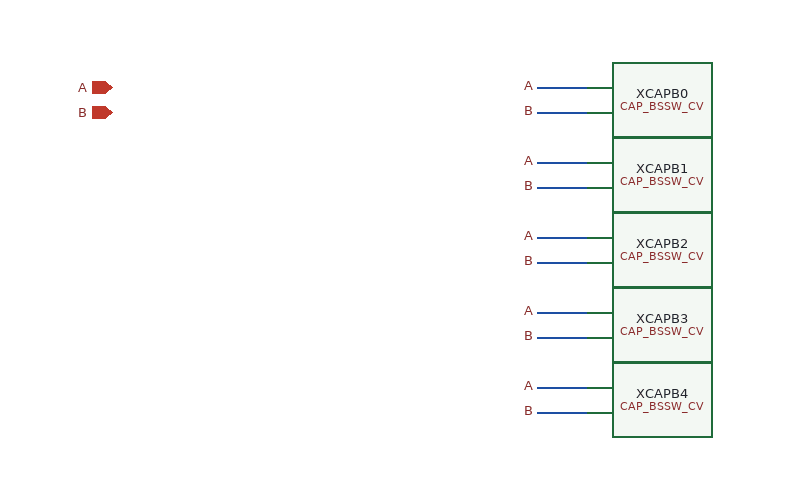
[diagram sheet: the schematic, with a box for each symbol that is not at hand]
v {xschem version=3.0.0 file_version=1.2 }
C {devices/iopin.sym} 0 0 0 0{name=p0 lab=A}
C {devices/iopin.sym} 0 20 0 0{name=p1 lab=B}
C {SUN_SAR9B_SK130NM/CAP_BSSW_CV.sym} 400 0 0 0 {name=XCAPB0}
N 340.0 0.0 380.0 0.0{lab=A}
C {devices/lab_pin.sym} 340.0 0.0 0 0  {name=l0 sig_type=std_logic lab=A }
N 340.0 20.0 380.0 20.0{lab=B}
C {devices/lab_pin.sym} 340.0 20.0 0 0  {name=l1 sig_type=std_logic lab=B }
C {SUN_SAR9B_SK130NM/CAP_BSSW_CV.sym} 400 60 0 0 {name=XCAPB1}
N 340.0 60.0 380.0 60.0{lab=A}
C {devices/lab_pin.sym} 340.0 60.0 0 0  {name=l2 sig_type=std_logic lab=A }
N 340.0 80.0 380.0 80.0{lab=B}
C {devices/lab_pin.sym} 340.0 80.0 0 0  {name=l3 sig_type=std_logic lab=B }
C {SUN_SAR9B_SK130NM/CAP_BSSW_CV.sym} 400 120 0 0 {name=XCAPB2}
N 340.0 120.0 380.0 120.0{lab=A}
C {devices/lab_pin.sym} 340.0 120.0 0 0  {name=l4 sig_type=std_logic lab=A }
N 340.0 140.0 380.0 140.0{lab=B}
C {devices/lab_pin.sym} 340.0 140.0 0 0  {name=l5 sig_type=std_logic lab=B }
C {SUN_SAR9B_SK130NM/CAP_BSSW_CV.sym} 400 180 0 0 {name=XCAPB3}
N 340.0 180.0 380.0 180.0{lab=A}
C {devices/lab_pin.sym} 340.0 180.0 0 0  {name=l6 sig_type=std_logic lab=A }
N 340.0 200.0 380.0 200.0{lab=B}
C {devices/lab_pin.sym} 340.0 200.0 0 0  {name=l7 sig_type=std_logic lab=B }
C {SUN_SAR9B_SK130NM/CAP_BSSW_CV.sym} 400 240 0 0 {name=XCAPB4}
N 340.0 240.0 380.0 240.0{lab=A}
C {devices/lab_pin.sym} 340.0 240.0 0 0  {name=l8 sig_type=std_logic lab=A }
N 340.0 260.0 380.0 260.0{lab=B}
C {devices/lab_pin.sym} 340.0 260.0 0 0  {name=l9 sig_type=std_logic lab=B }
